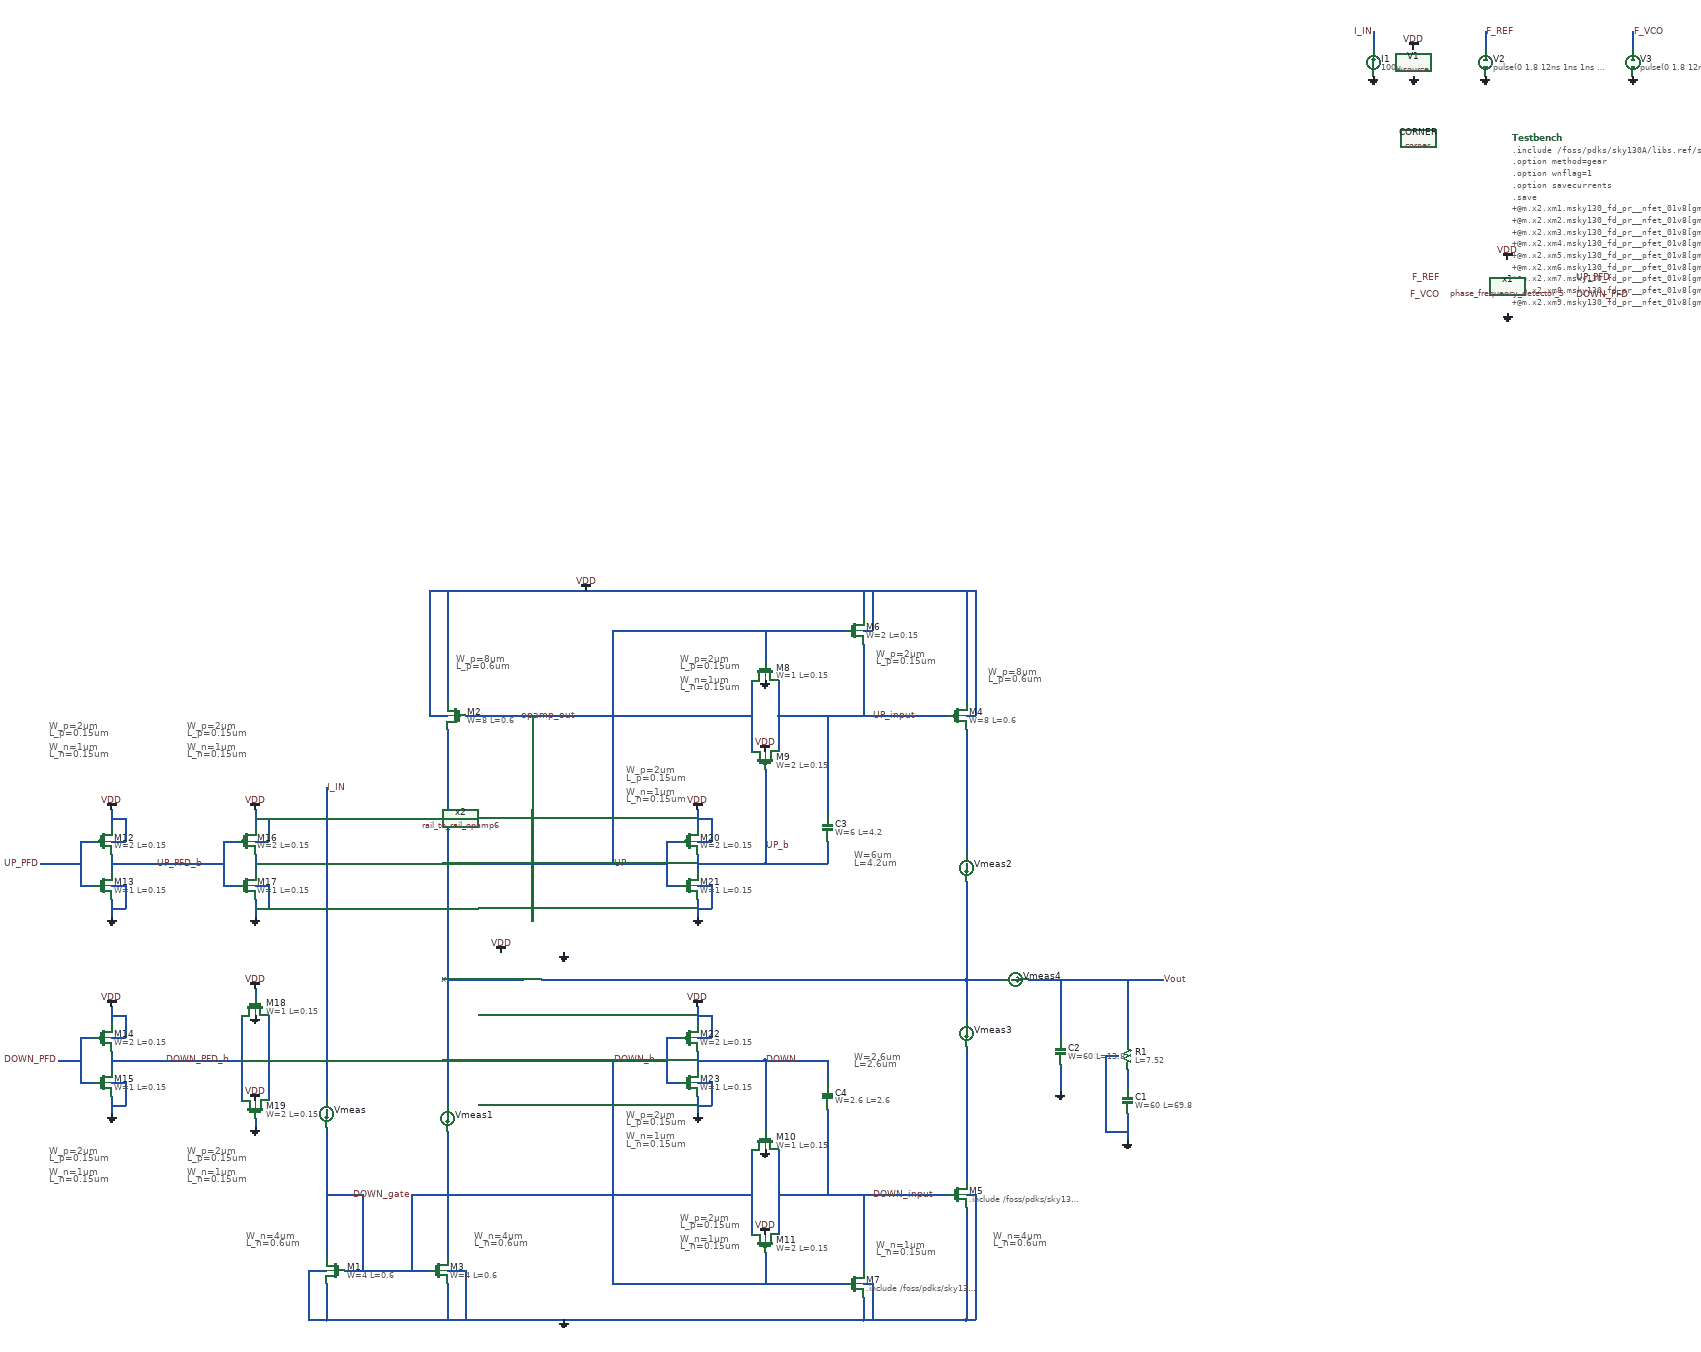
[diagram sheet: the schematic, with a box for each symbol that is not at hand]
v {xschem version=3.4.6 file_version=1.2}
G {}
K {}
V {}
S {}
E {}
B 2 4200 -3800 5560 -3140 {flags=graph
y1=0
y2=1.8
ypos1=0
ypos2=2
divy=5
subdivy=1
unity=1
x1=0
x2=5e-07
divx=5
subdivx=1
xlabmag=1.0
ylabmag=1.0


dataset=0
unitx=1
logx=0
logy=0








linewidth_mult=3







autoload=0
sim_type=tran
color="6 7"
node="f_ref
f_vco"}
B 2 4200 -2410 5580 -1730 {flags=graph
y1=-0.0045
y2=1.9
ypos1=0
ypos2=2
divy=5
subdivy=1
unity=1
x1=0
x2=5e-07
divx=5
subdivx=1
xlabmag=1.0
ylabmag=1.0


dataset=0
unitx=1
logx=0
logy=0








linewidth_mult=5





color="6 5"
node="up_pfd_b
down_pfd_b"}
B 2 4200 -3120 5580 -2420 {flags=graph
y1=-0.038
y2=1.9
ypos1=0
ypos2=2
divy=5
subdivy=1
unity=1
x1=0
x2=5e-07
divx=5
subdivx=1
xlabmag=1.0
ylabmag=1.0


dataset=0
unitx=1
logx=0
logy=0








linewidth_mult=5

color="6 5"
node="up_pfd
down_pfd"}
B 2 2440 -1870 3800 -1200 {flags=graph
y1=-4e-06
y2=1.7
ypos1=0
ypos2=2
divy=5
subdivy=1
unity=1
x1=0
x2=5e-07
divx=5
subdivx=1
xlabmag=1.0
ylabmag=1.0


dataset=0
unitx=1
logx=0
logy=0








linewidth_mult=4



color="19 7 6"
node="vout
x
opamp_out"}
B 2 4200 -1710 5580 -1030 {flags=graph
y1=-0.013
y2=1.9
ypos1=0
ypos2=2
divy=5
subdivy=1
unity=1
x1=0
x2=5e-07
divx=5
subdivx=1
xlabmag=1.0
ylabmag=1.0


dataset=0
unitx=1
logx=0
logy=0








linewidth_mult=5





color="6 5"
node="up
down_b"}
B 2 4200 -1010 5580 -330 {flags=graph
y1=-0.036
y2=1.9
ypos1=0
ypos2=2
divy=5
subdivy=1
unity=1
x1=0
x2=5e-07
divx=5
subdivx=1
xlabmag=1.0
ylabmag=1.0


dataset=0
unitx=1
logx=0
logy=0








linewidth_mult=5





color="6 5"
node="up_b
down"}
B 2 2440 -2570 3800 -1900 {flags=graph
y1=-4e-06
y2=1.7
ypos1=0
ypos2=2
divy=5
subdivy=1
unity=1
x1=0
x2=5e-07
divx=5
subdivx=1
xlabmag=1.0
ylabmag=1.0


dataset=0
unitx=1
logx=0
logy=0








linewidth_mult=4



color=6
node=vout}
B 2 2440 -3270 3800 -2600 {flags=graph
y1=7.3
y2=26
ypos1=0
ypos2=2
divy=5
subdivy=1
unity=1
x1=0
x2=5e-07
divx=5
subdivx=1
xlabmag=1.0
ylabmag=1.0


dataset=0
unitx=1
logx=0
logy=0








linewidth_mult=4



color="6 5"
node="\\"@m.x2.xm11.msky130_fd_pr__pfet_01v8[gm] i(@m.x2.xm11.msky130_fd_pr__pfet_01v8[id]) /\\"


\\"@m.x2.xm12.msky130_fd_pr__nfet_01v8[gm] i(@m.x2.xm12.msky130_fd_pr__nfet_01v8[id]) /\\""}
B 2 2440 -3980 3800 -3310 {flags=graph
y1=1.3e-09
y2=1.5e-05
ypos1=0
ypos2=2
divy=5
subdivy=1
unity=1
x1=0
x2=5e-07
divx=5
subdivx=1
xlabmag=1.0
ylabmag=1.0


dataset=0
unitx=1
logx=0
logy=0








linewidth_mult=4





color="6 7"
node="i(@m.x2.xm1.msky130_fd_pr__nfet_01v8[id])
i(@m.x2.xm6.msky130_fd_pr__pfet_01v8[id])"}
B 2 1040 -3980 2400 -3310 {flags=graph
y1=1.4e-10
y2=0.00014
ypos1=0
ypos2=2
divy=5
subdivy=1
unity=1
x1=0
x2=5e-07
divx=5
subdivx=1
xlabmag=1.0
ylabmag=1.0


dataset=0
unitx=1
logx=0
logy=0








linewidth_mult=4



color="6 7"
node="@m.x2.xm11.msky130_fd_pr__pfet_01v8[gm]


@m.x2.xm12.msky130_fd_pr__nfet_01v8[gm]"}
B 2 -380 -3980 980 -3310 {flags=graph
y1=1.3e-05
y2=1.5e-05
ypos1=0
ypos2=2
divy=5
subdivy=1
unity=1
x1=0
x2=5e-07
divx=5
subdivx=1
xlabmag=1.0
ylabmag=1.0


dataset=0
unitx=1
logx=0
logy=0








linewidth_mult=4




color=6
node=i(v.x2.vmeas)}
B 2 4190 780 5550 1450 {flags=graph
y1=-0.0087
y2=1.7
ypos1=0
ypos2=2
divy=5
subdivy=1
unity=1
x1=0
x2=5e-07
divx=5
subdivx=1
xlabmag=1.0
ylabmag=1.0


dataset=0
unitx=1
logx=0
logy=0








linewidth_mult=7



color="19 7 6"
node="vout
x
opamp_out"}
B 2 4190 80 5550 750 {flags=graph
y1=0.87
y2=0.89
ypos1=0
ypos2=2
divy=5
subdivy=1
unity=1
x1=0
x2=5e-07
divx=5
subdivx=1
xlabmag=1.0
ylabmag=1.0


dataset=0
unitx=1
logx=0
logy=0








linewidth_mult=7



color=6
node=vout}
B 2 4190 1480 5550 2150 {flags=graph
y1=-0.0001468
y2=9.22e-05
ypos1=0
ypos2=2
divy=5
subdivy=1
unity=1
x1=0
x2=5e-07
divx=5
subdivx=1
xlabmag=1.0
ylabmag=1.0


dataset=0
unitx=1
logx=0
logy=0








linewidth_mult=7




color="6 5"
node="i(vmeas2)
i(vmeas3)"}
B 2 1520 -750 2900 -70 {flags=graph
y1=-0.15
y2=1.9
ypos1=0
ypos2=2
divy=5
subdivy=1
unity=1
x1=0
x2=5e-07
divx=5
subdivx=1
xlabmag=1.0
ylabmag=1.0


dataset=0
unitx=1
logx=0
logy=0








linewidth_mult=5





color="6 5"
node="up_input
down_input"}
T {W_p=2um
L_p=0.15um

W_n=1um
L_n=0.15um} 320 540 0 0 0.4 0.4 {}
T {W_p=2um
L_p=0.15um

W_n=1um
L_n=0.15um} 320 1490 0 0 0.4 0.4 {}
T {W_p=2um
L_p=0.15um

W_n=1um
L_n=0.15um} 630 540 0 0 0.4 0.4 {}
T {W_p=2um
L_p=0.15um

W_n=1um
L_n=0.15um} 630 1490 0 0 0.4 0.4 {}
T {W_p=2um
L_p=0.15um

W_n=1um
L_n=0.15um} 1610 640 0 0 0.4 0.4 {}
T {W_p=2um
L_p=0.15um

W_n=1um
L_n=0.15um} 1610 1410 0 0 0.4 0.4 {}
T {W_n=4um
L_n=0.6um} 760 1680 0 0 0.4 0.4 {}
T {W_n=4um
L_n=0.6um} 1270 1680 0 0 0.4 0.4 {}
T {W_p=2um
L_p=0.15um

W_n=1um
L_n=0.15um} 1730 1640 0 0 0.4 0.4 {}
T {W_p=2um
L_p=0.15um

W_n=1um
L_n=0.15um} 1730 390 0 0 0.4 0.4 {}
T {W_p=8um
L_p=0.6um} 1230 390 0 0 0.4 0.4 {}
T {W_p=8um
L_p=0.6um} 2420 420 0 0 0.4 0.4 {}
T {W_n=4um
L_n=0.6um} 2430 1680 0 0 0.4 0.4 {}
T {W_n=1um
L_n=0.15um} 2170 1700 0 0 0.4 0.4 {}
T {W_p=2um
L_p=0.15um} 2170 380 0 0 0.4 0.4 {}
T {W=2.6um
L=2.6um} 2120 1280 0 0 0.4 0.4 {}
T {W=6um
L=4.2um} 2120 830 0 0 0.4 0.4 {}
N 2730 1320 2730 1370 {
lab=#net1}
N 2730 1120 2730 1260 {
lab=Vout}
N 2730 1420 2730 1480 {
lab=GND}
N 2680 1290 2710 1290 {
lab=GND}
N 2680 1290 2680 1460 {
lab=GND}
N 2680 1460 2730 1460 {
lab=GND}
N 2580 1120 2580 1260 {
lab=Vout}
N 2580 1310 2580 1370 {
lab=GND}
N 3530 -1000 3530 -960 {
lab=F_REF}
N 3860 -1000 3860 -960 {
lab=F_VCO}
N 2510 1120 2810 1120 {
lab=Vout}
N 3280 -1000 3280 -960 {
lab=I_IN}
N 980 1770 1170 1770 {
lab=DOWN_gate}
N 940 1800 940 1880 {
lab=GND}
N 940 1880 1500 1880 {
lab=GND}
N 900 1770 940 1770 {
lab=GND}
N 900 1770 900 1880 {
lab=GND}
N 900 1880 940 1880 {
lab=GND}
N 1210 1770 1250 1770 {
lab=GND}
N 1170 530 1210 530 {
lab=VDD}
N 1500 1880 1540 1880 {
lab=GND}
N 1210 250 1210 500 {
lab=VDD}
N 1170 250 1170 530 {
lab=VDD}
N 2370 250 2370 500 {
lab=VDD}
N 2140 250 2140 310 {
lab=VDD}
N 2140 340 2160 340 {
lab=VDD}
N 2160 250 2160 340 {
lab=VDD}
N 2390 250 2390 530 {
lab=VDD}
N 2370 530 2390 530 {
lab=VDD}
N 2370 560 2370 840 {
lab=#net2}
N 1540 1880 2140 1880 {
lab=GND}
N 2140 1830 2140 1880 {
lab=GND}
N 2370 1600 2390 1600 {
lab=GND}
N 2370 1880 2390 1880 {
lab=GND}
N 560 860 660 860 {
lab=UP_PFD_b}
N 600 1300 750 1300 {
lab=DOWN_PFD_b}
N 300 860 340 860 {
lab=UP_PFD}
N 340 1300 380 1300 {
lab=DOWN_PFD}
N 1210 560 1210 1000 {
lab=x}
N 1210 1120 1380 1120 {
lab=x}
N 1420 1120 2370 1120 {
lab=#net3}
N 1400 530 1400 990 {
lab=opamp_out}
N 1020 1600 1020 1770 {
lab=DOWN_gate}
N 940 1600 1020 1600 {
lab=DOWN_gate}
N 1250 1770 1250 1880 {
lab=GND}
N 1210 1800 1210 1880 {
lab=GND}
N 1130 1600 1890 1600 {
lab=DOWN_gate}
N 810 1300 1650 1300 {
lab=DOWN_b}
N 1920 650 1920 860 {
lab=UP_b}
N 1580 340 2100 340 {
lab=UP}
N 1580 340 1580 860 {
lab=UP}
N 2140 370 2140 530 {
lab=UP_input}
N 1950 530 2330 530 {
lab=UP_input}
N 1170 250 2390 250 {
lab=VDD}
N 1860 1300 1920 1300 {
lab=DOWN}
N 1920 1300 1920 1460 {
lab=DOWN}
N 1580 1300 1580 1800 {
lab=DOWN_b}
N 1580 1800 2100 1800 {
lab=DOWN_b}
N 750 1200 750 1390 {
lab=DOWN_PFD_b}
N 810 1200 810 1390 {
lab=DOWN_b}
N 780 1140 780 1160 {
lab=VDD}
N 780 1430 780 1450 {
lab=GND}
N 460 1280 460 1320 {
lab=DOWN_PFD_b}
N 390 1250 420 1250 {
lab=DOWN_PFD}
N 390 1250 390 1350 {
lab=DOWN_PFD}
N 390 1350 420 1350 {
lab=DOWN_PFD}
N 460 1300 600 1300 {
lab=DOWN_PFD_b}
N 380 1300 390 1300 {
lab=DOWN_PFD}
N 460 1380 460 1420 {
lab=GND}
N 460 1180 460 1220 {
lab=VDD}
N 460 1250 490 1250 {
lab=VDD}
N 490 1200 490 1250 {
lab=VDD}
N 460 1200 490 1200 {
lab=VDD}
N 460 1350 490 1350 {
lab=GND}
N 490 1350 490 1400 {
lab=GND}
N 460 1400 490 1400 {
lab=GND}
N 460 840 460 880 {
lab=UP_PFD_b}
N 390 810 420 810 {
lab=UP_PFD}
N 390 810 390 910 {
lab=UP_PFD}
N 390 910 420 910 {
lab=UP_PFD}
N 460 860 560 860 {
lab=UP_PFD_b}
N 340 860 390 860 {
lab=UP_PFD}
N 460 940 460 980 {
lab=GND}
N 460 740 460 780 {
lab=VDD}
N 460 810 490 810 {
lab=VDD}
N 490 760 490 810 {
lab=VDD}
N 460 760 490 760 {
lab=VDD}
N 460 910 490 910 {
lab=GND}
N 490 910 490 960 {
lab=GND}
N 460 960 490 960 {
lab=GND}
N 780 840 780 880 {
lab=UP}
N 710 810 740 810 {
lab=UP_PFD_b}
N 710 810 710 910 {
lab=UP_PFD_b}
N 710 910 740 910 {
lab=UP_PFD_b}
N 660 860 710 860 {
lab=UP_PFD_b}
N 780 940 780 980 {
lab=GND}
N 780 740 780 780 {
lab=VDD}
N 780 810 810 810 {
lab=VDD}
N 810 760 810 810 {
lab=VDD}
N 780 760 810 760 {
lab=VDD}
N 780 910 810 910 {
lab=GND}
N 810 910 810 960 {
lab=GND}
N 780 960 810 960 {
lab=GND}
N 1770 1280 1770 1320 {
lab=DOWN}
N 1700 1250 1730 1250 {
lab=DOWN_b}
N 1700 1250 1700 1350 {
lab=DOWN_b}
N 1700 1350 1730 1350 {
lab=DOWN_b}
N 1650 1300 1700 1300 {
lab=DOWN_b}
N 1770 1380 1770 1420 {
lab=GND}
N 1770 1180 1770 1220 {
lab=VDD}
N 1770 1250 1800 1250 {
lab=VDD}
N 1800 1200 1800 1250 {
lab=VDD}
N 1770 1200 1800 1200 {
lab=VDD}
N 1770 1350 1800 1350 {
lab=GND}
N 1800 1350 1800 1400 {
lab=GND}
N 1770 1400 1800 1400 {
lab=GND}
N 1770 1300 1860 1300 {
lab=DOWN}
N 1770 840 1770 880 {
lab=UP_b}
N 1700 810 1730 810 {
lab=UP}
N 1700 810 1700 910 {
lab=UP}
N 1700 910 1730 910 {
lab=UP}
N 1580 860 1700 860 {
lab=UP}
N 1770 940 1770 980 {
lab=GND}
N 1770 740 1770 780 {
lab=VDD}
N 1770 810 1800 810 {
lab=VDD}
N 1800 760 1800 810 {
lab=VDD}
N 1770 760 1800 760 {
lab=VDD}
N 1770 910 1800 910 {
lab=GND}
N 1800 910 1800 960 {
lab=GND}
N 1770 960 1800 960 {
lab=GND}
N 1770 860 1860 860 {
lab=UP_b}
N 1860 860 1920 860 {
lab=UP_b}
N 780 860 1580 860 {
lab=UP}
N 1210 1000 1210 1060 {
lab=x}
N 940 690 940 1390 {
lab=I_IN}
N 1210 1060 1210 1400 {
lab=x}
N 1210 1480 1210 1740 {
lab=#net4}
N 940 1450 940 1460 {
lab=DOWN_gate}
N 940 1560 940 1740 {
lab=DOWN_gate}
N 1210 1460 1210 1480 {
lab=#net4}
N 940 1460 940 1560 {
lab=DOWN_gate}
N 1950 450 1950 530 {
lab=UP_input}
N 1890 450 1890 610 {
lab=opamp_out}
N 1950 530 1950 610 {
lab=UP_input}
N 1250 530 1890 530 {
lab=opamp_out}
N 2140 1880 2370 1880 {
lab=GND}
N 1950 1500 1950 1690 {
lab=DOWN_input}
N 1890 1500 1890 1690 {
lab=DOWN_gate}
N 1950 1600 2330 1600 {
lab=DOWN_input}
N 2370 1630 2370 1880 {
lab=GND}
N 2390 1600 2390 1880 {
lab=GND}
N 1130 1600 1130 1770 {
lab=DOWN_gate}
N 2140 1600 2140 1770 {
lab=DOWN_input}
N 2140 1800 2160 1800 {
lab=GND}
N 2160 1800 2160 1880 {
lab=GND}
N 1920 340 1920 410 {
lab=UP}
N 2370 1270 2370 1570 {
lab=#net5}
N 2370 1120 2370 1210 {
lab=#net3}
N 2370 900 2370 1120 {
lab=#net3}
N 1920 860 2060 860 {
lab=UP_b}
N 2060 810 2060 860 {
lab=UP_b}
N 2060 530 2060 750 {
lab=UP_input}
N 2060 1300 2060 1350 {
lab=DOWN}
N 2060 1410 2060 1600 {
lab=DOWN_input}
N 1920 1300 2060 1300 {
lab=DOWN}
N 2370 1120 2450 1120 {
lab=#net3}
N 1920 1730 1920 1800 {
lab=DOWN_b}
C {sky130_fd_pr/corner.sym} 3380 -760 0 0 {name=CORNER only_toplevel=false corner=tt
value="

.include /foss/pdks/sky130A/libs.ref/sky130_fd_sc_hd/spice/sky130_fd_sc_hd.spice

.option method=gear
.option wnflag=1

* V_out initial voltage value for the F_VCO delay of 2ns  (leading)
* .ic v(vout) = 1.8

* V_out initial voltage value for the F_VCO delay of 12ns (lock condition)
.ic v(vout) = 0.83

* V_out initial voltage value for the F_VCO delay of 22ns (lagging)
* .ic v(vout) = 0

.control
  save v(f_ref) save v(f_vco) save v(i_in) save v(up_pfd) v(down_pfd) v(up_pfd_b) v(down_pfd_b) v(up) v(up_b) v(down) v(down_b) v(x) v(opamp_out) v(up_input) v(down_input) v(down_gate) v(vout)

  * timestep for exact simulation results
  * tran 5ps 0.5us

  * timestep for faster simulation results
  tran 50ps 0.5us

  remzerovec
  write pfd_charge_pump_10.raw
  set appendwrite

.endc

"


v(vout)="0.0

.control
  save all

  * timestep for exact simulation results
  tran 5ps 0.5us

  * timestep for faster simulation results
  * tran 50ps 0.5us

  remzerovec
  write pfd_chargA}
C {devices/code.sym} 3590 -761.25 0 0 {name=Testbench only_toplevel=false value="

.include /foss/pdks/sky130A/libs.ref/sky130_fd_sc_hd/spice/sky130_fd_sc_hd.spice

.option method=gear
.option wnflag=1
.option savecurrents

.save
+@m.x2.xm1.msky130_fd_pr__nfet_01v8[gm]
+@m.x2.xm2.msky130_fd_pr__nfet_01v8[gm]
+@m.x2.xm3.msky130_fd_pr__nfet_01v8[gm]
+@m.x2.xm4.msky130_fd_pr__pfet_01v8[gm]
+@m.x2.xm5.msky130_fd_pr__pfet_01v8[gm]
+@m.x2.xm6.msky130_fd_pr__pfet_01v8[gm]
+@m.x2.xm7.msky130_fd_pr__pfet_01v8[gm]
+@m.x2.xm8.msky130_fd_pr__pfet_01v8[gm]
+@m.x2.xm9.msky130_fd_pr__nfet_01v8[gm]
+@m.x2.xm10.msky130_fd_pr__nfet_01v8[gm]
+@m.x2.xm11.msky130_fd_pr__pfet_01v8[gm]
+@m.x2.xm12.msky130_fd_pr__nfet_01v8[gm]
+@m.x2.xm13.msky130_fd_pr__pfet_01v8[gm]
+@m.x2.xm15.msky130_fd_pr__nfet_01v8[gm]

* V_out initial voltage value for the F_VCO delay of 2ns  (leading)
* .ic v(vout) = 1.8

* V_out initial voltage value for the F_VCO delay of 12ns (lock condition)
.ic v(vout) = 0.9

* V_out initial voltage value for the F_VCO delay of 22ns (lagging)
* .ic v(vout) = 0.0

.control
  * save v(f_ref) save v(f_vco) save v(i_in) save v(up_pfd) v(down_pfd) v(up_pfd_b) v(down_pfd_b) v(up) v(up_b) v(down) v(down_b) v(x) v(opamp_out) v(up_input) v(down_input) v(down_gate) v(vout)
  save all

  * timestep for exact simulation results
  * tran 5ps 0.5us

  * timestep for faster simulation results
  tran 50ps 0.5us

  remzerovec
  write pfd_charge_pump_10.raw
  * write pfd_charge_pump_10_2.raw
  * write pfd_charge_pump_10_3.raw
  * write pfd_charge_pump_10_4.raw
  * write pfd_charge_pump_10_5.raw
  * write pfd_charge_pump_10_6.raw
  * write pfd_charge_pump_10_7.raw
  * write pfd_charge_pump_10_8.raw
  * write pfd_charge_pump_10_9.raw
  * write pfd_charge_pump_10_10.raw
  set appendwrite

.endc

"
}
C {devices/vsource.sym} 3370 -930 0 0 {name=V1 value=1.8 savecurrent=false}
C {devices/gnd.sym} 3370 -900 0 0 {name=l2 lab=GND}
C {devices/vdd.sym} 3370 -960 0 1 {name=l3 lab=VDD}
C {devices/lab_wire.sym} 2810 1120 0 1 {name=p9 sig_type=std_logic lab=Vout}
C {sky130_fd_pr/cap_mim_m3_1.sym} 2580 1280 0 0 {name=C2 model=cap_mim_m3_1 W=60 L=13.8 MF=1 spiceprefix=X}
C {sky130_fd_pr/cap_mim_m3_1.sym} 2730 1390 0 0 {name=C1 model=cap_mim_m3_1 W=60 L=69.8 MF=1 spiceprefix=X}
C {devices/gnd.sym} 2730 1480 0 0 {name=l4 lab=GND
value="

.include /foss/pdks/sky130A/libs.ref/sky130_fd_sc_hd/spice/sky130_fd_sc_hd.spice

.option method=gear
.option wnflag=1

* V_out initial voltage value for the F_VCO delay of 2ns  (leading)
* .ic v(vout) = 1.8

* V_out initial voltage value for the F_VCO delay of 12ns (lock condition)
.ic v(vout) = 0.83

* V_out initial voltage value for the F_VCO delay of 22ns (lagging)
* .ic v(vout) = 0

.control
  save v(f_ref) save v(f_vco) save v(i_in) save v(up_pfd) v(down_pfd) v(up_pfd_b) v(down_pfd_b) v(up) v(up_b) v(down) v(down_b) v(x) v(opamp_out) v(up_input) v(down_input) v(down_gate) v(vout)

  * timestep for exact simulation results
  * tran 5ps 0.5us

  * timestep for faster simulation results
  tran 50ps 0.5us

  remzerovec
  write pfd_charge_pump_10.raw
  set appendwrite

.endc

"}
C {devices/gnd.sym} 2580 1370 0 0 {name=l9 lab=GND
W=60}
C {devices/vsource.sym} 3530 -930 0 0 {name=V2 value=pulse"(0 1.8 12ns 1ns 1ns 24ns 50ns)" savecurrent=false
* }
C {devices/gnd.sym} 3530 -900 0 0 {name=l10 lab=GND}
C {devices/lab_pin.sym} 3530 -1000 0 1 {name=p11 sig_type=std_logic lab=F_REF}
C {devices/vsource.sym} 3860 -930 0 0 {name=V3 value="pulse(0 1.8 12ns 1ns 1ns 24ns 50ns)" savecurrent=false
* "sin(0.9 0.9 20.1MEG)" 1 AC 1}
C {devices/gnd.sym} 3860 -900 0 0 {name=l15 lab=GND}
C {devices/lab_pin.sym} 3860 -1000 0 1 {name=p12 sig_type=std_logic lab=F_VCO}
C {devices/lab_pin.sym} 3430 -450 0 0 {name=p19 lab=F_REF
value="

.include /foss/pdks/sky130A/libs.ref/sky130_fd_sc_hd/spice/sky130_fd_sc_hd.spice

.option method=gear
.option wnflag=1

* V_out initial voltage value for the F_VCO delay of 2ns  (leading)
* .ic v(vout) = 1.8

* V_out initial voltage value for the F_VCO delay of 12ns (lock condition)
.ic v(vout) = 0.83

* V_out initial voltage value for the F_VCO delay of 22ns (lagging)
* .ic v(vout) = 0

.control
  save v(f_ref) save v(f_vco) save v(i_in) save v(up_pfd) v(down_pfd) v(up_pfd_b) v(down_pfd_b) v(up) v(up_b) v(down) v(down_b) v(x) v(opamp_out) v(up_input) v(down_input) v(down_gate) v(vout)

  * timestep for exact simulation results
  * tran 5ps 0.5us

  * timestep for faster simulation results
  tran 50ps 0.5us

  remzerovec
  write pfd_charge_pump_10.raw
  set appendwrite

.endc

"


v(vout)="0.0

.control
  save all

  * timestep for exact simulation results
  tran 5ps 0.5us

  * timestep for faster simulation results
  * tran 50ps 0.5us

  remzerovec
  write pfd_charge_pump_10.raw
  set appA}
C {devices/lab_pin.sym} 3430 -410 0 0 {name=p20 lab=F_VCO
value="

.include /foss/pdks/sky130A/libs.ref/sky130_fd_sc_hd/spice/sky130_fd_sc_hd.spice

.option method=gear
.option wnflag=1

* V_out initial voltage value for the F_VCO delay of 2ns  (leading)
* .ic v(vout) = 1.8

* V_out initial voltage value for the F_VCO delay of 12ns (lock condition)
.ic v(vout) = 0.83

* V_out initial voltage value for the F_VCO delay of 22ns (lagging)
* .ic v(vout) = 0

.control
  save v(f_ref) save v(f_vco) save v(i_in) save v(up_pfd) v(down_pfd) v(up_pfd_b) v(down_pfd_b) v(up) v(up_b) v(down) v(down_b) v(x) v(opamp_out) v(up_input) v(down_input) v(down_gate) v(vout)

  * timestep for exact simulation results
  * tran 5ps 0.5us

  * timestep for faster simulation results
  tran 50ps 0.5us

  remzerovec
  write pfd_charge_pump_10.raw
  set appendwrite

.endc

"


v(vout)="0.0

.control
  save all

  * timestep for exact simulation results
  tran 5ps 0.5us

  * timestep for faster simulation results
  * tran 50ps 0.5us

  remzerovec
  write pfd_charge_pump_10.raw
  set appA}
C {devices/lab_wire.sym} 3730 -450 0 1 {name=p22 sig_type=std_logic lab=UP_PFD}
C {devices/lab_wire.sym} 3730 -410 2 0 {name=p23 sig_type=std_logic lab=DOWN_PFD}
C {devices/vdd.sym} 3580 -490 0 1 {name=l1 lab=VDD
value="

.include /foss/pdks/sky130A/libs.ref/sky130_fd_sc_hd/spice/sky130_fd_sc_hd.spice

.option method=gear
.option wnflag=1

* V_out initial voltage value for the F_VCO delay of 2ns  (leading)
* .ic v(vout) = 1.8

* V_out initial voltage value for the F_VCO delay of 12ns (lock condition)
.ic v(vout) = 0.83

* V_out initial voltage value for the F_VCO delay of 22ns (lagging)
* .ic v(vout) = 0

.control
  save v(f_ref) save v(f_vco) save v(i_in) save v(up_pfd) v(down_pfd) v(up_pfd_b) v(down_pfd_b) v(up) v(up_b) v(down) v(down_b) v(x) v(opamp_out) v(up_input) v(down_input) v(down_gate) v(vout)

  * timestep for exact simulation results
  * tran 5ps 0.5us

  * timestep for faster simulation results
  tran 50ps 0.5us

  remzerovec
  write pfd_charge_pump_10.raw
  set appendwrite

.endc

"


v(vout)="0.0

.control
  save all

  * timestep for exact simulation results
  tran 5ps 0.5us

  * timestep for faster simulation results
  * tran 50ps 0.5us

  remzerovec
  write pfd_charge_pump_10.raw
  set appendA}
C {devices/gnd.sym} 3580 -370 0 0 {name=l8 lab=GND
value="

.include /foss/pdks/sky130A/libs.ref/sky130_fd_sc_hd/spice/sky130_fd_sc_hd.spice

.option method=gear
.option wnflag=1

* V_out initial voltage value for the F_VCO delay of 2ns  (leading)
* .ic v(vout) = 1.8

* V_out initial voltage value for the F_VCO delay of 12ns (lock condition)
.ic v(vout) = 0.83

* V_out initial voltage value for the F_VCO delay of 22ns (lagging)
* .ic v(vout) = 0

.control
  save v(f_ref) save v(f_vco) save v(i_in) save v(up_pfd) v(down_pfd) v(up_pfd_b) v(down_pfd_b) v(up) v(up_b) v(down) v(down_b) v(x) v(opamp_out) v(up_input) v(down_input) v(down_gate) v(vout)

  * timestep for exact simulation results
  * tran 5ps 0.5us

  * timestep for faster simulation results
  tran 50ps 0.5us

  remzerovec
  write pfd_charge_pump_10.raw
  set appendwrite

.endc

"}
C {sky130_fd_pr/res_xhigh_po_0p35.sym} 2730 1290 0 0 {name=R1
L=7.52
model=res_xhigh_po_0p35
spiceprefix=X
mult=1}
C {devices/isource.sym} 3280 -930 2 0 {name=I1 value=100u}
C {devices/gnd.sym} 3280 -900 0 0 {name=l26 lab=GND}
C {devices/lab_pin.sym} 3280 -1000 2 1 {name=p3 sig_type=std_logic lab=I_IN}
C {devices/ammeter.sym} 2370 1240 0 0 {name=Vmeas3 savecurrent=true spice_ignore=0}
C {sky130_fd_pr/nfet_01v8.sym} 960 1770 0 1 {name=M1
L=0.6
W=4
nf=1 
mult=1
ad="'int((nf+1)/2) * W/nf * 0.29'" 
pd="'2*int((nf+1)/2) * (W/nf + 0.29)'"
as="'int((nf+2)/2) * W/nf * 0.29'" 
ps="'2*int((nf+2)/2) * (W/nf + 0.29)'"
nrd="'0.29 / W'" nrs="'0.29 / W'"
sa=0 sb=0 sd=0
model=nfet_01v8
spiceprefix=X
}
C {sky130_fd_pr/nfet_01v8.sym} 1190 1770 0 0 {name=M3
L=0.6
W=4
nf=1 
mult=1
ad="'int((nf+1)/2) * W/nf * 0.29'" 
pd="'2*int((nf+1)/2) * (W/nf + 0.29)'"
as="'int((nf+2)/2) * W/nf * 0.29'" 
ps="'2*int((nf+2)/2) * (W/nf + 0.29)'"
nrd="'0.29 / W'" nrs="'0.29 / W'"
sa=0 sb=0 sd=0
model=nfet_01v8
spiceprefix=X
}
C {sky130_fd_pr/pfet_01v8.sym} 1230 530 2 0 {name=M2
L=0.6
W=8
nf=8
mult=1
ad="'int((nf+1)/2) * W/nf * 0.29'" 
pd="'2*int((nf+1)/2) * (W/nf + 0.29)'"
as="'int((nf+2)/2) * W/nf * 0.29'" 
ps="'2*int((nf+2)/2) * (W/nf + 0.29)'"
nrd="'0.29 / W'" nrs="'0.29 / W'"
sa=0 sb=0 sd=0
model=pfet_01v8
spiceprefix=X
}
C {devices/vdd.sym} 1520 250 0 0 {name=l13 lab=VDD}
C {devices/gnd.sym} 1470 1880 0 0 {name=l14 lab=GND}
C {devices/lab_wire.sym} 1210 1120 0 0 {name=p2 sig_type=std_logic lab=x}
C {sky130_fd_pr/pfet_01v8.sym} 1920 630 1 1 {name=M9
L=0.15
W=2
nf=2
mult=1
ad="'int((nf+1)/2) * W/nf * 0.29'" 
pd="'2*int((nf+1)/2) * (W/nf + 0.29)'"
as="'int((nf+2)/2) * W/nf * 0.29'" 
ps="'2*int((nf+2)/2) * (W/nf + 0.29)'"
nrd="'0.29 / W'" nrs="'0.29 / W'"
sa=0 sb=0 sd=0
model=pfet_01v8
spiceprefix=X
}
C {sky130_fd_pr/pfet_01v8.sym} 2120 340 0 0 {name=M6
L=0.15
W=2
nf=2
mult=1
ad="'int((nf+1)/2) * W/nf * 0.29'" 
pd="'2*int((nf+1)/2) * (W/nf + 0.29)'"
as="'int((nf+2)/2) * W/nf * 0.29'" 
ps="'2*int((nf+2)/2) * (W/nf + 0.29)'"
nrd="'0.29 / W'" nrs="'0.29 / W'"
sa=0 sb=0 sd=0
model=pfet_01v8
spiceprefix=X
}
C {sky130_fd_pr/pfet_01v8.sym} 2350 530 0 0 {name=M4
L=0.6
W=8
nf=8
mult=1
ad="'int((nf+1)/2) * W/nf * 0.29'" 
pd="'2*int((nf+1)/2) * (W/nf + 0.29)'"
as="'int((nf+2)/2) * W/nf * 0.29'" 
ps="'2*int((nf+2)/2) * (W/nf + 0.29)'"
nrd="'0.29 / W'" nrs="'0.29 / W'"
sa=0 sb=0 sd=0
model=pfet_01v8
spiceprefix=X
}
C {devices/lab_wire.sym} 1580 860 2 0 {name=p4 sig_type=std_logic lab=UP}
C {devices/lab_wire.sym} 1920 820 0 1 {name=p5 sig_type=std_logic lab=UP_b}
C {sky130_fd_pr/nfet_01v8.sym} 1920 1480 1 0 {name=M10
L=0.15
W=1
nf=1 
mult=1
ad="'int((nf+1)/2) * W/nf * 0.29'" 
pd="'2*int((nf+1)/2) * (W/nf + 0.29)'"
as="'int((nf+2)/2) * W/nf * 0.29'" 
ps="'2*int((nf+2)/2) * (W/nf + 0.29)'"
nrd="'0.29 / W'" nrs="'0.29 / W'"
sa=0 sb=0 sd=0
model=nfet_01v8
spiceprefix=X
}
C {sky130_fd_pr/nfet_01v8.sym} 2120 1800 0 0 {name=M7
L=0.15
W=1
nf=1 
mult=1
ad="'int((nf+1)/2) * W/nf * 0.29'" 
pd="'2*int((nf+1)/2) * (W/nf + 0.29)'"
as="'int((nf+2)/2) * W/nf * 0.29'" 
ps="'2*int((nf+2)/2) * (W/nf + 0.29)'"
nrd="'0.29 / W'" nrs="'0.29 / W'"
sa=0 sb=0 sd=0
model=nfet_01v8
spiceprefix=X
value="

.include /foss/pdks/sky130A/libs.ref/sky130_fd_sc_hd/spice/sky130_fd_sc_hd.spice

.option method=gear
.option wnflag=1

* V_out initial voltage value for the F_VCO delay of 2ns  (leading)
* .ic v(vout) = 1.8

* V_out initial voltage value for the F_VCO delay of 12ns (lock condition)
.ic v(vout) = 0.83

* V_out initial voltage value for the F_VCO delay of 22ns (lagging)
* .ic v(vout) = 0

.control
  save v(f_ref) save v(f_vco) save v(i_in) save v(up_pfd) v(down_pfd) v(up_pfd_b) v(down_pfd_b) v(up) v(up_b) v(down) v(down_b) v(x) v(opamp_out) v(up_input) v(down_input) v(down_gate) v(vout)

  * timestep for exact simulation results
  * tran 5ps 0.5us

  * timestep for faster simulation results
  tran 50ps 0.5us

  remzerovec
  write pfd_charge_pump_10.raw
  set appendwrite

.endc

"}
C {devices/lab_wire.sym} 1580 1300 0 1 {name=p6 sig_type=std_logic lab=DOWN_b}
C {sky130_fd_pr/nfet_01v8.sym} 2350 1600 0 0 {name=M5
L=0.6
W=4
nf=1 
mult=1
ad="'int((nf+1)/2) * W/nf * 0.29'" 
pd="'2*int((nf+1)/2) * (W/nf + 0.29)'"
as="'int((nf+2)/2) * W/nf * 0.29'" 
ps="'2*int((nf+2)/2) * (W/nf + 0.29)'"
nrd="'0.29 / W'" nrs="'0.29 / W'"
sa=0 sb=0 sd=0
model=nfet_01v8
spiceprefix=X
value="

.include /foss/pdks/sky130A/libs.ref/sky130_fd_sc_hd/spice/sky130_fd_sc_hd.spice

.option method=gear
.option wnflag=1

* V_out initial voltage value for the F_VCO delay of 2ns  (leading)
* .ic v(vout) = 1.8

* V_out initial voltage value for the F_VCO delay of 12ns (lock condition)
.ic v(vout) = 0.83

* V_out initial voltage value for the F_VCO delay of 22ns (lagging)
* .ic v(vout) = 0

.control
  save v(f_ref) save v(f_vco) save v(i_in) save v(up_pfd) v(down_pfd) v(up_pfd_b) v(down_pfd_b) v(up) v(up_b) v(down) v(down_b) v(x) v(opamp_out) v(up_input) v(down_input) v(down_gate) v(vout)

  * timestep for exact simulation results
  * tran 5ps 0.5us

  * timestep for faster simulation results
  tran 50ps 0.5us

  remzerovec
  write pfd_charge_pump_10.raw
  set appendwrite

.endc

"}
C {devices/lab_wire.sym} 560 860 0 1 {name=p15 sig_type=std_logic lab=UP_PFD_b}
C {devices/lab_wire.sym} 2160 530 2 0 {name=p13 sig_type=std_logic lab=UP_input}
C {devices/lab_wire.sym} 2160 1600 0 1 {name=p14 sig_type=std_logic lab=DOWN_input
value="

.include /foss/pdks/sky130A/libs.ref/sky130_fd_sc_hd/spice/sky130_fd_sc_hd.spice

.option method=gear
.option wnflag=1

* V_out initial voltage value for the F_VCO delay of 2ns  (leading)
* .ic v(vout) = 1.8

* V_out initial voltage value for the F_VCO delay of 12ns (lock condition)
.ic v(vout) = 0.83

* V_out initial voltage value for the F_VCO delay of 22ns (lagging)
* .ic v(vout) = 0

.control
  save v(f_ref) save v(f_vco) save v(i_in) save v(up_pfd) v(down_pfd) v(up_pfd_b) v(down_pfd_b) v(up) v(up_b) v(down) v(down_b) v(x) v(opamp_out) v(up_input) v(down_input) v(down_gate) v(vout)

  * timestep for exact simulation results
  * tran 5ps 0.5us

  * timestep for faster simulation results
  tran 50ps 0.5us

  remzerovec
  write pfd_charge_pump_10.raw
  set appendwrite

.endc

"}
C {devices/gnd.sym} 1470 1060 0 0 {name=l7 lab=GND}
C {devices/lab_wire.sym} 1500 530 0 0 {name=p17 sig_type=std_logic lab=opamp_out}
C {devices/lab_wire.sym} 300 860 0 0 {name=p7 sig_type=std_logic lab=UP_PFD}
C {devices/lab_wire.sym} 340 1300 2 1 {name=p8 sig_type=std_logic lab=DOWN_PFD}
C {devices/vdd.sym} 1330 1060 0 1 {name=l6 lab=VDD}
C {sky130_fd_pr/pfet_01v8.sym} 780 1410 3 0 {name=M19
L=0.15
W=2
nf=2
mult=1
ad="'int((nf+1)/2) * W/nf * 0.29'" 
pd="'2*int((nf+1)/2) * (W/nf + 0.29)'"
as="'int((nf+2)/2) * W/nf * 0.29'" 
ps="'2*int((nf+2)/2) * (W/nf + 0.29)'"
nrd="'0.29 / W'" nrs="'0.29 / W'"
sa=0 sb=0 sd=0
model=pfet_01v8
spiceprefix=X
}
C {sky130_fd_pr/nfet_01v8.sym} 780 1180 1 0 {name=M18
L=0.15
W=1
nf=1 
mult=1
ad="'int((nf+1)/2) * W/nf * 0.29'" 
pd="'2*int((nf+1)/2) * (W/nf + 0.29)'"
as="'int((nf+2)/2) * W/nf * 0.29'" 
ps="'2*int((nf+2)/2) * (W/nf + 0.29)'"
nrd="'0.29 / W'" nrs="'0.29 / W'"
sa=0 sb=0 sd=0
model=nfet_01v8
spiceprefix=X
}
C {devices/vdd.sym} 780 1140 0 0 {name=l11 lab=VDD}
C {devices/gnd.sym} 780 1450 0 0 {name=l12 lab=GND}
C {sky130_fd_pr/pfet_01v8.sym} 440 1250 0 0 {name=M14
L=0.15
W=2
nf=2
mult=1
ad="'int((nf+1)/2) * W/nf * 0.29'" 
pd="'2*int((nf+1)/2) * (W/nf + 0.29)'"
as="'int((nf+2)/2) * W/nf * 0.29'" 
ps="'2*int((nf+2)/2) * (W/nf + 0.29)'"
nrd="'0.29 / W'" nrs="'0.29 / W'"
sa=0 sb=0 sd=0
model=pfet_01v8
spiceprefix=X
}
C {sky130_fd_pr/nfet_01v8.sym} 440 1350 2 1 {name=M15
L=0.15
W=1
nf=1 
mult=1
ad="'int((nf+1)/2) * W/nf * 0.29'" 
pd="'2*int((nf+1)/2) * (W/nf + 0.29)'"
as="'int((nf+2)/2) * W/nf * 0.29'" 
ps="'2*int((nf+2)/2) * (W/nf + 0.29)'"
nrd="'0.29 / W'" nrs="'0.29 / W'"
sa=0 sb=0 sd=0
model=nfet_01v8
spiceprefix=X
}
C {devices/gnd.sym} 460 1420 0 0 {name=l16 lab=GND}
C {devices/vdd.sym} 460 1180 0 0 {name=l17 lab=VDD}
C {sky130_fd_pr/pfet_01v8.sym} 440 810 0 0 {name=M12
L=0.15
W=2
nf=2
mult=1
ad="'int((nf+1)/2) * W/nf * 0.29'" 
pd="'2*int((nf+1)/2) * (W/nf + 0.29)'"
as="'int((nf+2)/2) * W/nf * 0.29'" 
ps="'2*int((nf+2)/2) * (W/nf + 0.29)'"
nrd="'0.29 / W'" nrs="'0.29 / W'"
sa=0 sb=0 sd=0
model=pfet_01v8
spiceprefix=X
}
C {sky130_fd_pr/nfet_01v8.sym} 440 910 2 1 {name=M13
L=0.15
W=1
nf=1 
mult=1
ad="'int((nf+1)/2) * W/nf * 0.29'" 
pd="'2*int((nf+1)/2) * (W/nf + 0.29)'"
as="'int((nf+2)/2) * W/nf * 0.29'" 
ps="'2*int((nf+2)/2) * (W/nf + 0.29)'"
nrd="'0.29 / W'" nrs="'0.29 / W'"
sa=0 sb=0 sd=0
model=nfet_01v8
spiceprefix=X
}
C {devices/gnd.sym} 460 980 0 0 {name=l18 lab=GND}
C {devices/vdd.sym} 460 740 0 0 {name=l19 lab=VDD}
C {sky130_fd_pr/pfet_01v8.sym} 760 810 0 0 {name=M16
L=0.15
W=2
nf=2
mult=1
ad="'int((nf+1)/2) * W/nf * 0.29'" 
pd="'2*int((nf+1)/2) * (W/nf + 0.29)'"
as="'int((nf+2)/2) * W/nf * 0.29'" 
ps="'2*int((nf+2)/2) * (W/nf + 0.29)'"
nrd="'0.29 / W'" nrs="'0.29 / W'"
sa=0 sb=0 sd=0
model=pfet_01v8
spiceprefix=X
}
C {sky130_fd_pr/nfet_01v8.sym} 760 910 2 1 {name=M17
L=0.15
W=1
nf=1 
mult=1
ad="'int((nf+1)/2) * W/nf * 0.29'" 
pd="'2*int((nf+1)/2) * (W/nf + 0.29)'"
as="'int((nf+2)/2) * W/nf * 0.29'" 
ps="'2*int((nf+2)/2) * (W/nf + 0.29)'"
nrd="'0.29 / W'" nrs="'0.29 / W'"
sa=0 sb=0 sd=0
model=nfet_01v8
spiceprefix=X
}
C {devices/gnd.sym} 780 980 0 0 {name=l20 lab=GND}
C {devices/vdd.sym} 780 740 0 0 {name=l21 lab=VDD}
C {sky130_fd_pr/pfet_01v8.sym} 1750 1250 0 0 {name=M22
L=0.15
W=2
nf=2
mult=1
ad="'int((nf+1)/2) * W/nf * 0.29'" 
pd="'2*int((nf+1)/2) * (W/nf + 0.29)'"
as="'int((nf+2)/2) * W/nf * 0.29'" 
ps="'2*int((nf+2)/2) * (W/nf + 0.29)'"
nrd="'0.29 / W'" nrs="'0.29 / W'"
sa=0 sb=0 sd=0
model=pfet_01v8
spiceprefix=X
}
C {sky130_fd_pr/nfet_01v8.sym} 1750 1350 2 1 {name=M23
L=0.15
W=1
nf=1 
mult=1
ad="'int((nf+1)/2) * W/nf * 0.29'" 
pd="'2*int((nf+1)/2) * (W/nf + 0.29)'"
as="'int((nf+2)/2) * W/nf * 0.29'" 
ps="'2*int((nf+2)/2) * (W/nf + 0.29)'"
nrd="'0.29 / W'" nrs="'0.29 / W'"
sa=0 sb=0 sd=0
model=nfet_01v8
spiceprefix=X
}
C {devices/gnd.sym} 1770 1420 0 0 {name=l22 lab=GND}
C {devices/vdd.sym} 1770 1180 0 0 {name=l23 lab=VDD}
C {sky130_fd_pr/pfet_01v8.sym} 1750 810 0 0 {name=M20
L=0.15
W=2
nf=2
mult=1
ad="'int((nf+1)/2) * W/nf * 0.29'" 
pd="'2*int((nf+1)/2) * (W/nf + 0.29)'"
as="'int((nf+2)/2) * W/nf * 0.29'" 
ps="'2*int((nf+2)/2) * (W/nf + 0.29)'"
nrd="'0.29 / W'" nrs="'0.29 / W'"
sa=0 sb=0 sd=0
model=pfet_01v8
spiceprefix=X
}
C {sky130_fd_pr/nfet_01v8.sym} 1750 910 2 1 {name=M21
L=0.15
W=1
nf=1 
mult=1
ad="'int((nf+1)/2) * W/nf * 0.29'" 
pd="'2*int((nf+1)/2) * (W/nf + 0.29)'"
as="'int((nf+2)/2) * W/nf * 0.29'" 
ps="'2*int((nf+2)/2) * (W/nf + 0.29)'"
nrd="'0.29 / W'" nrs="'0.29 / W'"
sa=0 sb=0 sd=0
model=nfet_01v8
spiceprefix=X
}
C {devices/gnd.sym} 1770 980 0 0 {name=l24 lab=GND}
C {devices/vdd.sym} 1770 740 0 0 {name=l25 lab=VDD}
C {devices/lab_wire.sym} 940 690 0 1 {name=p16 sig_type=std_logic lab=I_IN}
C {devices/ammeter.sym} 940 1420 0 0 {name=Vmeas savecurrent=true spice_ignore=0}
C {devices/ammeter.sym} 1210 1430 0 0 {name=Vmeas1 savecurrent=true spice_ignore=0}
C {devices/lab_wire.sym} 580 1300 2 0 {name=p10 sig_type=std_logic lab=DOWN_PFD_b}
C {devices/lab_wire.sym} 1920 1300 0 1 {name=p21 sig_type=std_logic lab=DOWN}
C {devices/ammeter.sym} 2370 870 0 0 {name=Vmeas2 savecurrent=true spice_ignore=0}
C {devices/ammeter.sym} 2480 1120 3 0 {name=Vmeas4 savecurrent=true spice_ignore=0}
C {sky130_fd_pr/nfet_01v8.sym} 1920 430 1 0 {name=M8
L=0.15
W=1
nf=1 
mult=1
ad="'int((nf+1)/2) * W/nf * 0.29'" 
pd="'2*int((nf+1)/2) * (W/nf + 0.29)'"
as="'int((nf+2)/2) * W/nf * 0.29'" 
ps="'2*int((nf+2)/2) * (W/nf + 0.29)'"
nrd="'0.29 / W'" nrs="'0.29 / W'"
sa=0 sb=0 sd=0
model=nfet_01v8
spiceprefix=X
}
C {sky130_fd_pr/pfet_01v8.sym} 1920 1710 1 1 {name=M11
L=0.15
W=2
nf=2
mult=1
ad="'int((nf+1)/2) * W/nf * 0.29'" 
pd="'2*int((nf+1)/2) * (W/nf + 0.29)'"
as="'int((nf+2)/2) * W/nf * 0.29'" 
ps="'2*int((nf+2)/2) * (W/nf + 0.29)'"
nrd="'0.29 / W'" nrs="'0.29 / W'"
sa=0 sb=0 sd=0
model=pfet_01v8
spiceprefix=X
}
C {devices/vdd.sym} 1920 610 0 0 {name=l5 lab=VDD}
C {devices/gnd.sym} 1920 450 0 0 {name=l27 lab=GND}
C {devices/gnd.sym} 1920 1500 0 0 {name=l28 lab=GND}
C {devices/vdd.sym} 1920 1690 0 0 {name=l29 lab=VDD}
C {devices/gnd.sym} 780 1200 0 0 {name=l30 lab=GND}
C {devices/vdd.sym} 780 1390 0 0 {name=l31 lab=VDD}
C {devices/lab_wire.sym} 1130 1600 0 0 {name=p18 sig_type=std_logic lab=DOWN_gate}
C {/foss/designs/my_design/projects/pll/pfd/xschem_ngspice/phase_frequency_detector_5.sym} 3580 -430 0 0 {name=x1}
C {sky130_fd_pr/cap_mim_m3_1.sym} 2060 780 0 0 {name=C3 model=cap_mim_m3_1 W=6 L=4.2 MF=1 spiceprefix=X}
C {sky130_fd_pr/cap_mim_m3_1.sym} 2060 1380 0 0 {name=C4 model=cap_mim_m3_1 W=2.6 L=2.6 MF=1 spiceprefix=X}
C {/foss/designs/my_design/projects/pll/charge_pump/xschem_ngspice/rail_to_rail_opamp6.sym} 1400 1060 3 0 {name=x2}
